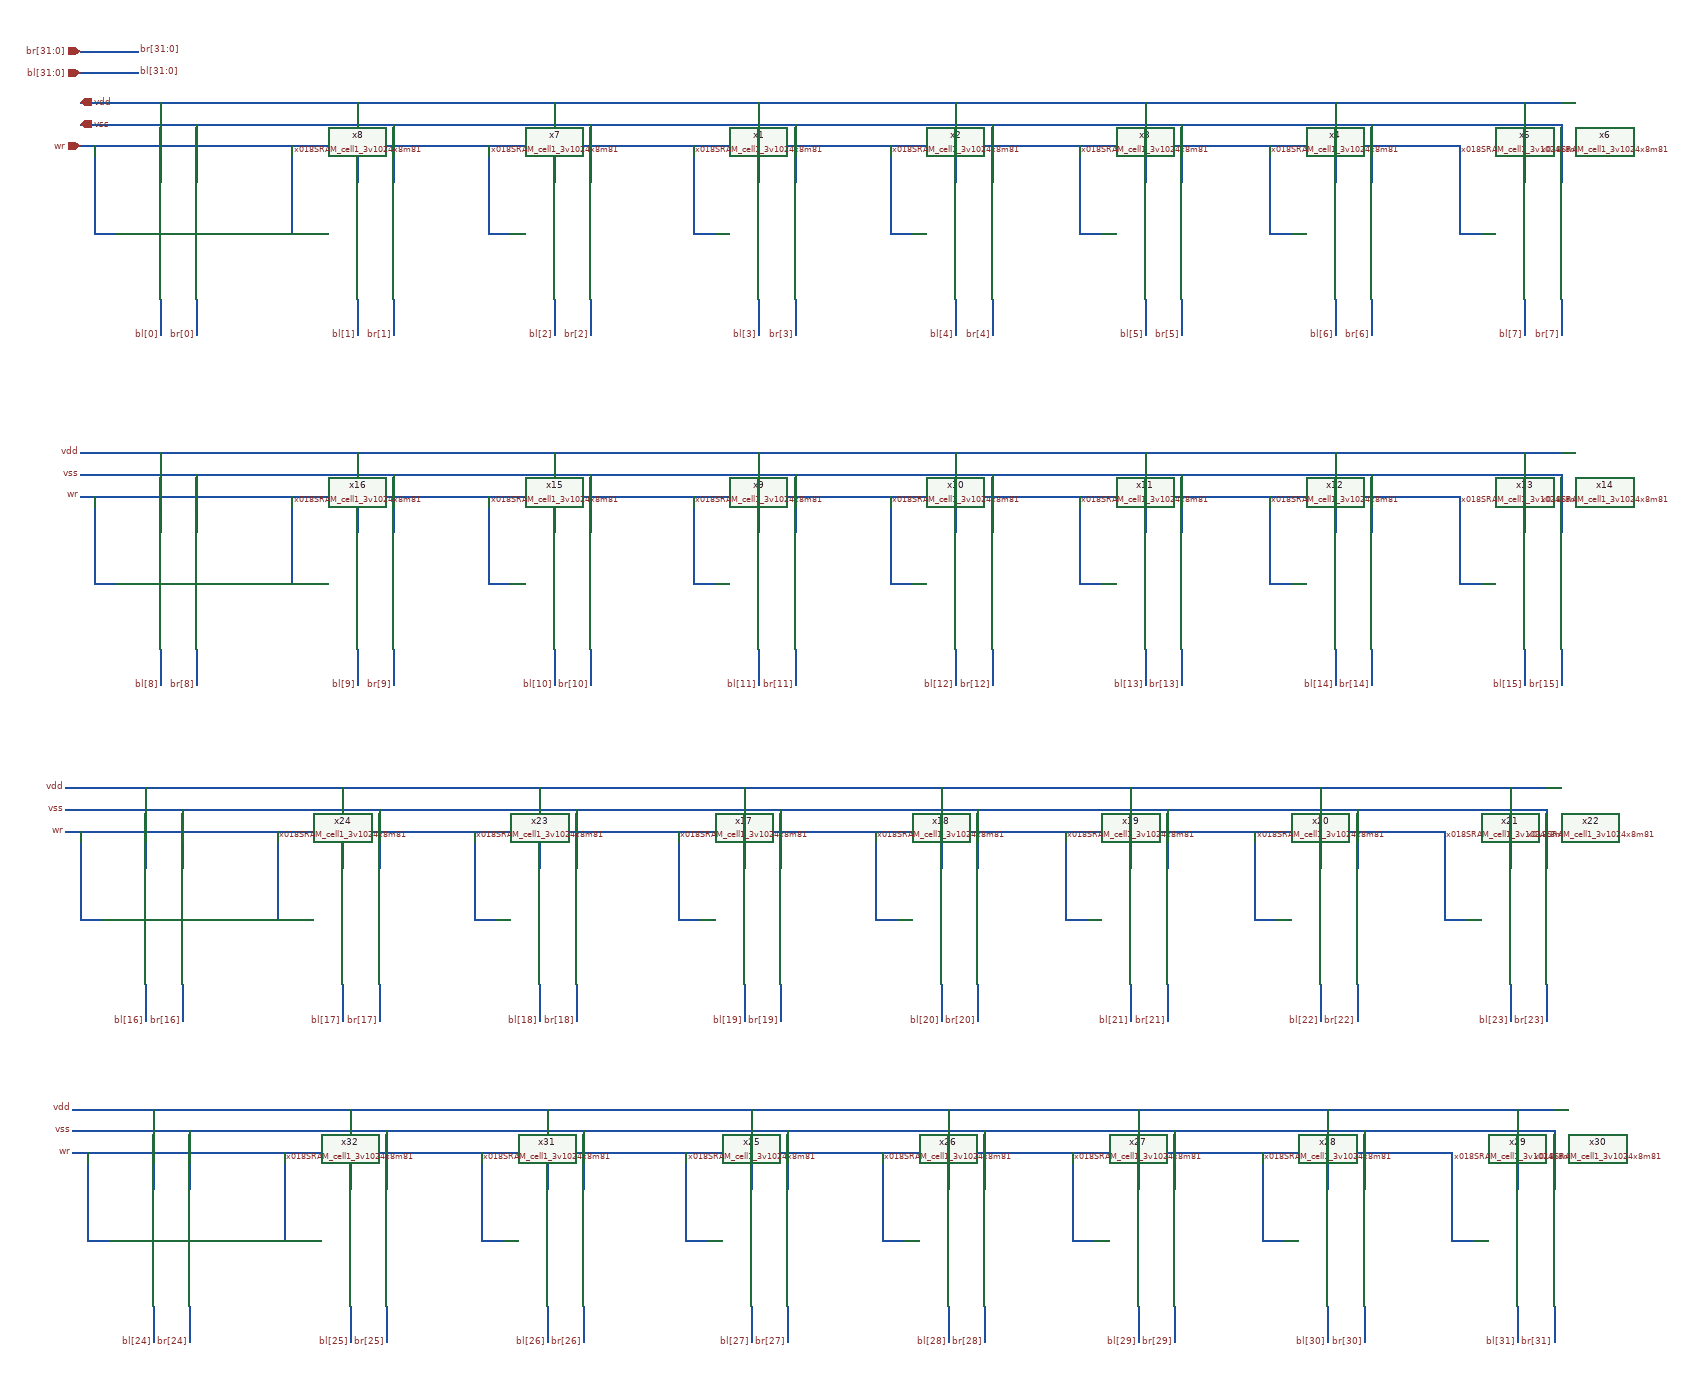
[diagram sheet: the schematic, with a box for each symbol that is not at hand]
v {xschem version=3.4.6 file_version=1.2}
G {}
K {}
V {}
S {}
E {}
N -770 -60 1260 -60 {lab=vss}
N -770 -90 1260 -90 {lab=vdd}
N -750 -30 -750 90 {lab=wr}
N -750 90 -720 90 {lab=wr}
N -660 -90 -660 20 {lab=vdd}
N -610 -60 -610 20 {lab=vss}
N -480 -30 -480 90 {lab=wr}
N -480 90 -450 90 {lab=wr}
N -390 -90 -390 20 {lab=vdd}
N -340 -60 -340 20 {lab=vss}
N -210 -30 -210 90 {lab=wr}
N -210 90 -180 90 {lab=wr}
N -120 -90 -120 20 {lab=vdd}
N -70 -60 -70 20 {lab=vss}
N 70 -30 70 90 {lab=wr}
N 70 90 100 90 {lab=wr}
N 160 -90 160 20 {lab=vdd}
N 210 -60 210 20 {lab=vss}
N 340 -30 340 90 {lab=wr}
N 340 90 370 90 {lab=wr}
N 430 -90 430 20 {lab=vdd}
N 480 -60 480 20 {lab=vss}
N 600 -30 600 90 {lab=wr}
N 600 90 630 90 {lab=wr}
N 690 -90 690 20 {lab=vdd}
N 740 -60 740 20 {lab=vss}
N 860 -30 860 90 {lab=wr}
N 860 90 890 90 {lab=wr}
N 950 -90 950 20 {lab=vdd}
N 1000 -60 1000 20 {lab=vss}
N 1120 -30 1120 90 {lab=wr}
N 1120 90 1150 90 {lab=wr}
N 1210 -90 1210 20 {lab=vdd}
N -660 180 -660 230 {lab=bl[0]}
N -610 180 -610 230 {lab=br[0]}
N -390 180 -390 230 {lab=bl[1]}
N -340 180 -340 230 {lab=br[1]}
N -120 180 -120 230 {lab=bl[2]}
N -70 180 -70 230 {lab=br[2]}
N 160 180 160 230 {lab=bl[3]}
N 210 180 210 230 {lab=br[3]}
N 430 180 430 230 {lab=bl[4]}
N 480 180 480 230 {lab=br[4]}
N 690 180 690 230 {lab=bl[5]}
N 740 180 740 230 {lab=br[5]}
N 950 180 950 230 {lab=bl[6]}
N 1000 180 1000 230 {lab=br[6]}
N 1210 180 1210 230 {lab=bl[7]}
N 1260 180 1260 230 {lab=br[7]}
N -770 -130 -690 -130 {lab=bl[31:0]}
N -770 -160 -690 -160 {lab=br[31:0]}
N -770 420 1260 420 {lab=vss}
N -770 390 1260 390 {lab=vdd}
N -750 450 -750 570 {lab=wr}
N -750 570 -720 570 {lab=wr}
N -660 390 -660 500 {lab=vdd}
N -610 420 -610 500 {lab=vss}
N -480 450 -480 570 {lab=wr}
N -480 570 -450 570 {lab=wr}
N -390 390 -390 500 {lab=vdd}
N -340 420 -340 500 {lab=vss}
N -210 450 -210 570 {lab=wr}
N -210 570 -180 570 {lab=wr}
N -120 390 -120 500 {lab=vdd}
N -70 420 -70 500 {lab=vss}
N 70 450 70 570 {lab=wr}
N 70 570 100 570 {lab=wr}
N 160 390 160 500 {lab=vdd}
N 210 420 210 500 {lab=vss}
N 340 450 340 570 {lab=wr}
N 340 570 370 570 {lab=wr}
N 430 390 430 500 {lab=vdd}
N 480 420 480 500 {lab=vss}
N 600 450 600 570 {lab=wr}
N 600 570 630 570 {lab=wr}
N 690 390 690 500 {lab=vdd}
N 740 420 740 500 {lab=vss}
N 860 450 860 570 {lab=wr}
N 860 570 890 570 {lab=wr}
N 950 390 950 500 {lab=vdd}
N 1000 420 1000 500 {lab=vss}
N 1120 450 1120 570 {lab=wr}
N 1120 570 1150 570 {lab=wr}
N 1210 390 1210 500 {lab=vdd}
N -660 660 -660 710 {lab=bl[8]}
N -610 660 -610 710 {lab=br[8]}
N -390 660 -390 710 {lab=bl[9]}
N -340 660 -340 710 {lab=br[9]}
N -120 660 -120 710 {lab=bl[10]}
N -70 660 -70 710 {lab=br[10]}
N 160 660 160 710 {lab=bl[11]}
N 210 660 210 710 {lab=br[11]}
N 430 660 430 710 {lab=bl[12]}
N 480 660 480 710 {lab=br[12]}
N 690 660 690 710 {lab=bl[13]}
N 740 660 740 710 {lab=br[13]}
N 950 660 950 710 {lab=bl[14]}
N 1000 660 1000 710 {lab=br[14]}
N 1210 660 1210 710 {lab=bl[15]}
N 1260 660 1260 710 {lab=br[15]}
N -790 880 1240 880 {lab=vss}
N -790 850 1240 850 {lab=vdd}
N -770 910 -770 1030 {lab=wr}
N -770 1030 -740 1030 {lab=wr}
N -680 850 -680 960 {lab=vdd}
N -630 880 -630 960 {lab=vss}
N -500 910 -500 1030 {lab=wr}
N -500 1030 -470 1030 {lab=wr}
N -410 850 -410 960 {lab=vdd}
N -360 880 -360 960 {lab=vss}
N -230 910 -230 1030 {lab=wr}
N -230 1030 -200 1030 {lab=wr}
N -140 850 -140 960 {lab=vdd}
N -90 880 -90 960 {lab=vss}
N 50 910 50 1030 {lab=wr}
N 50 1030 80 1030 {lab=wr}
N 140 850 140 960 {lab=vdd}
N 190 880 190 960 {lab=vss}
N 320 910 320 1030 {lab=wr}
N 320 1030 350 1030 {lab=wr}
N 410 850 410 960 {lab=vdd}
N 460 880 460 960 {lab=vss}
N 580 910 580 1030 {lab=wr}
N 580 1030 610 1030 {lab=wr}
N 670 850 670 960 {lab=vdd}
N 720 880 720 960 {lab=vss}
N 840 910 840 1030 {lab=wr}
N 840 1030 870 1030 {lab=wr}
N 930 850 930 960 {lab=vdd}
N 980 880 980 960 {lab=vss}
N 1100 910 1100 1030 {lab=wr}
N 1100 1030 1130 1030 {lab=wr}
N 1190 850 1190 960 {lab=vdd}
N -680 1120 -680 1170 {lab=bl[16]}
N -630 1120 -630 1170 {lab=br[16]}
N -410 1120 -410 1170 {lab=bl[17]}
N -360 1120 -360 1170 {lab=br[17]}
N -140 1120 -140 1170 {lab=bl[18]}
N -90 1120 -90 1170 {lab=br[18]}
N 140 1120 140 1170 {lab=bl[19]}
N 190 1120 190 1170 {lab=br[19]}
N 410 1120 410 1170 {lab=bl[20]}
N 460 1120 460 1170 {lab=br[20]}
N 670 1120 670 1170 {lab=bl[21]}
N 720 1120 720 1170 {lab=br[21]}
N 930 1120 930 1170 {lab=bl[22]}
N 980 1120 980 1170 {lab=br[22]}
N 1190 1120 1190 1170 {lab=bl[23]}
N 1240 1120 1240 1170 {lab=br[23]}
N -780 1320 1250 1320 {lab=vss}
N -780 1290 1250 1290 {lab=vdd}
N -760 1350 -760 1470 {lab=wr}
N -760 1470 -730 1470 {lab=wr}
N -670 1290 -670 1400 {lab=vdd}
N -620 1320 -620 1400 {lab=vss}
N -490 1350 -490 1470 {lab=wr}
N -490 1470 -460 1470 {lab=wr}
N -400 1290 -400 1400 {lab=vdd}
N -350 1320 -350 1400 {lab=vss}
N -220 1350 -220 1470 {lab=wr}
N -220 1470 -190 1470 {lab=wr}
N -130 1290 -130 1400 {lab=vdd}
N -80 1320 -80 1400 {lab=vss}
N 60 1350 60 1470 {lab=wr}
N 60 1470 90 1470 {lab=wr}
N 150 1290 150 1400 {lab=vdd}
N 200 1320 200 1400 {lab=vss}
N 330 1350 330 1470 {lab=wr}
N 330 1470 360 1470 {lab=wr}
N 420 1290 420 1400 {lab=vdd}
N 470 1320 470 1400 {lab=vss}
N 590 1350 590 1470 {lab=wr}
N 590 1470 620 1470 {lab=wr}
N 680 1290 680 1400 {lab=vdd}
N 730 1320 730 1400 {lab=vss}
N 850 1350 850 1470 {lab=wr}
N 850 1470 880 1470 {lab=wr}
N 940 1290 940 1400 {lab=vdd}
N 990 1320 990 1400 {lab=vss}
N 1110 1350 1110 1470 {lab=wr}
N 1110 1470 1140 1470 {lab=wr}
N 1200 1290 1200 1400 {lab=vdd}
N -670 1560 -670 1610 {lab=bl[24]}
N -620 1560 -620 1610 {lab=br[24]}
N -400 1560 -400 1610 {lab=bl[25]}
N -350 1560 -350 1610 {lab=br[25]}
N -130 1560 -130 1610 {lab=bl[26]}
N -80 1560 -80 1610 {lab=br[26]}
N 150 1560 150 1610 {lab=bl[27]}
N 200 1560 200 1610 {lab=br[27]}
N 420 1560 420 1610 {lab=bl[28]}
N 470 1560 470 1610 {lab=br[28]}
N 680 1560 680 1610 {lab=bl[29]}
N 730 1560 730 1610 {lab=br[29]}
N 940 1560 940 1610 {lab=bl[30]}
N 990 1560 990 1610 {lab=br[30]}
N 1200 1560 1200 1610 {lab=bl[31]}
N 1250 1560 1250 1610 {lab=br[31]}
N -770 -30 1120 -30 {lab=wr}
N -770 450 1120 450 {lab=wr}
N -790 910 1100 910 {lab=wr}
N -780 1350 1110 1350 {lab=wr}
N 1260 -60 1260 20 {lab=vss}
N 1260 420 1260 500 {lab=vss}
N 1240 880 1240 960 {lab=vss}
N 1250 1320 1250 1400 {lab=vss}
C {x018SRAM_cell1_3v1024x8m81.sym} -30 70 0 0 {name=x1}
C {x018SRAM_cell1_3v1024x8m81.sym} 250 70 0 0 {name=x2}
C {x018SRAM_cell1_3v1024x8m81.sym} 520 70 0 0 {name=x3}
C {x018SRAM_cell1_3v1024x8m81.sym} 780 70 0 0 {name=x4}
C {x018SRAM_cell1_3v1024x8m81.sym} 1040 70 0 0 {name=x5}
C {x018SRAM_cell1_3v1024x8m81.sym} 1300 70 0 0 {name=x6}
C {x018SRAM_cell1_3v1024x8m81.sym} -300 70 0 0 {name=x7}
C {x018SRAM_cell1_3v1024x8m81.sym} -570 70 0 0 {name=x8}
C {iopin.sym} -770 -90 0 1 {name=p1 lab=vdd}
C {iopin.sym} -770 -60 0 1 {name=p2 lab=vss}
C {ipin.sym} -770 -30 0 0 {name=p3 lab=wr}
C {iopin.sym} -770 -130 2 0 {name=p4 lab=bl[31:0]}
C {iopin.sym} -770 -160 2 0 {name=p5 lab=br[31:0]}
C {lab_pin.sym} -690 -160 0 1 {name=p6 sig_type=std_logic lab=br[31:0]}
C {lab_pin.sym} -690 -130 0 1 {name=p7 sig_type=std_logic lab=bl[31:0]}
C {lab_pin.sym} -660 230 3 0 {name=p8 sig_type=std_logic lab=bl[0]}
C {lab_pin.sym} -610 230 3 0 {name=p9 sig_type=std_logic lab=br[0]}
C {lab_pin.sym} -390 230 3 0 {name=p10 sig_type=std_logic lab=bl[1]}
C {lab_pin.sym} -340 230 3 0 {name=p11 sig_type=std_logic lab=br[1]}
C {lab_pin.sym} -120 230 3 0 {name=p12 sig_type=std_logic lab=bl[2]}
C {lab_pin.sym} -70 230 3 0 {name=p13 sig_type=std_logic lab=br[2]}
C {lab_pin.sym} 160 230 3 0 {name=p14 sig_type=std_logic lab=bl[3]}
C {lab_pin.sym} 210 230 3 0 {name=p15 sig_type=std_logic lab=br[3]}
C {lab_pin.sym} 430 230 3 0 {name=p16 sig_type=std_logic lab=bl[4]}
C {lab_pin.sym} 480 230 3 0 {name=p17 sig_type=std_logic lab=br[4]}
C {lab_pin.sym} 690 230 3 0 {name=p18 sig_type=std_logic lab=bl[5]}
C {lab_pin.sym} 740 230 3 0 {name=p19 sig_type=std_logic lab=br[5]}
C {lab_pin.sym} 950 230 3 0 {name=p20 sig_type=std_logic lab=bl[6]}
C {lab_pin.sym} 1000 230 3 0 {name=p21 sig_type=std_logic lab=br[6]}
C {lab_pin.sym} 1210 230 3 0 {name=p22 sig_type=std_logic lab=bl[7]}
C {lab_pin.sym} 1260 230 3 0 {name=p23 sig_type=std_logic lab=br[7]}
C {x018SRAM_cell1_3v1024x8m81.sym} -30 550 0 0 {name=x9}
C {x018SRAM_cell1_3v1024x8m81.sym} 250 550 0 0 {name=x10}
C {x018SRAM_cell1_3v1024x8m81.sym} 520 550 0 0 {name=x11}
C {x018SRAM_cell1_3v1024x8m81.sym} 780 550 0 0 {name=x12}
C {x018SRAM_cell1_3v1024x8m81.sym} 1040 550 0 0 {name=x13}
C {x018SRAM_cell1_3v1024x8m81.sym} 1300 550 0 0 {name=x14}
C {x018SRAM_cell1_3v1024x8m81.sym} -300 550 0 0 {name=x15}
C {x018SRAM_cell1_3v1024x8m81.sym} -570 550 0 0 {name=x16}
C {lab_pin.sym} -660 710 3 0 {name=p31 sig_type=std_logic lab=bl[8]}
C {lab_pin.sym} -610 710 3 0 {name=p32 sig_type=std_logic lab=br[8]}
C {lab_pin.sym} -390 710 3 0 {name=p33 sig_type=std_logic lab=bl[9]}
C {lab_pin.sym} -340 710 3 0 {name=p34 sig_type=std_logic lab=br[9]}
C {lab_pin.sym} -120 710 3 0 {name=p35 sig_type=std_logic lab=bl[10]}
C {lab_pin.sym} -70 710 3 0 {name=p36 sig_type=std_logic lab=br[10]}
C {lab_pin.sym} 160 710 3 0 {name=p37 sig_type=std_logic lab=bl[11]}
C {lab_pin.sym} 210 710 3 0 {name=p38 sig_type=std_logic lab=br[11]}
C {lab_pin.sym} 430 710 3 0 {name=p39 sig_type=std_logic lab=bl[12]}
C {lab_pin.sym} 480 710 3 0 {name=p40 sig_type=std_logic lab=br[12]}
C {lab_pin.sym} 690 710 3 0 {name=p41 sig_type=std_logic lab=bl[13]}
C {lab_pin.sym} 740 710 3 0 {name=p42 sig_type=std_logic lab=br[13]}
C {lab_pin.sym} 950 710 3 0 {name=p43 sig_type=std_logic lab=bl[14]}
C {lab_pin.sym} 1000 710 3 0 {name=p44 sig_type=std_logic lab=br[14]}
C {lab_pin.sym} 1210 710 3 0 {name=p45 sig_type=std_logic lab=bl[15]}
C {lab_pin.sym} 1260 710 3 0 {name=p46 sig_type=std_logic lab=br[15]}
C {lab_pin.sym} -770 390 0 0 {name=p24 sig_type=std_logic lab=vdd}
C {lab_pin.sym} -770 420 0 0 {name=p25 sig_type=std_logic lab=vss}
C {lab_pin.sym} -770 450 0 0 {name=p26 sig_type=std_logic lab=wr}
C {x018SRAM_cell1_3v1024x8m81.sym} -50 1010 0 0 {name=x17}
C {x018SRAM_cell1_3v1024x8m81.sym} 230 1010 0 0 {name=x18}
C {x018SRAM_cell1_3v1024x8m81.sym} 500 1010 0 0 {name=x19}
C {x018SRAM_cell1_3v1024x8m81.sym} 760 1010 0 0 {name=x20}
C {x018SRAM_cell1_3v1024x8m81.sym} 1020 1010 0 0 {name=x21}
C {x018SRAM_cell1_3v1024x8m81.sym} 1280 1010 0 0 {name=x22}
C {x018SRAM_cell1_3v1024x8m81.sym} -320 1010 0 0 {name=x23}
C {x018SRAM_cell1_3v1024x8m81.sym} -590 1010 0 0 {name=x24}
C {lab_pin.sym} -680 1170 3 0 {name=p27 sig_type=std_logic lab=bl[16]}
C {lab_pin.sym} -630 1170 3 0 {name=p28 sig_type=std_logic lab=br[16]}
C {lab_pin.sym} -410 1170 3 0 {name=p29 sig_type=std_logic lab=bl[17]}
C {lab_pin.sym} -360 1170 3 0 {name=p30 sig_type=std_logic lab=br[17]}
C {lab_pin.sym} -140 1170 3 0 {name=p47 sig_type=std_logic lab=bl[18]}
C {lab_pin.sym} -90 1170 3 0 {name=p48 sig_type=std_logic lab=br[18]}
C {lab_pin.sym} 140 1170 3 0 {name=p49 sig_type=std_logic lab=bl[19]}
C {lab_pin.sym} 190 1170 3 0 {name=p50 sig_type=std_logic lab=br[19]}
C {lab_pin.sym} 410 1170 3 0 {name=p51 sig_type=std_logic lab=bl[20]}
C {lab_pin.sym} 460 1170 3 0 {name=p52 sig_type=std_logic lab=br[20]}
C {lab_pin.sym} 670 1170 3 0 {name=p53 sig_type=std_logic lab=bl[21]}
C {lab_pin.sym} 720 1170 3 0 {name=p54 sig_type=std_logic lab=br[21]}
C {lab_pin.sym} 930 1170 3 0 {name=p55 sig_type=std_logic lab=bl[22]}
C {lab_pin.sym} 980 1170 3 0 {name=p56 sig_type=std_logic lab=br[22]}
C {lab_pin.sym} 1190 1170 3 0 {name=p57 sig_type=std_logic lab=bl[23]}
C {lab_pin.sym} 1240 1170 3 0 {name=p58 sig_type=std_logic lab=br[23]}
C {lab_pin.sym} -790 850 0 0 {name=p59 sig_type=std_logic lab=vdd}
C {lab_pin.sym} -790 880 0 0 {name=p60 sig_type=std_logic lab=vss}
C {lab_pin.sym} -790 910 0 0 {name=p61 sig_type=std_logic lab=wr}
C {x018SRAM_cell1_3v1024x8m81.sym} -40 1450 0 0 {name=x25}
C {x018SRAM_cell1_3v1024x8m81.sym} 240 1450 0 0 {name=x26}
C {x018SRAM_cell1_3v1024x8m81.sym} 510 1450 0 0 {name=x27}
C {x018SRAM_cell1_3v1024x8m81.sym} 770 1450 0 0 {name=x28}
C {x018SRAM_cell1_3v1024x8m81.sym} 1030 1450 0 0 {name=x29}
C {x018SRAM_cell1_3v1024x8m81.sym} 1290 1450 0 0 {name=x30}
C {x018SRAM_cell1_3v1024x8m81.sym} -310 1450 0 0 {name=x31}
C {x018SRAM_cell1_3v1024x8m81.sym} -580 1450 0 0 {name=x32}
C {lab_pin.sym} -670 1610 3 0 {name=p62 sig_type=std_logic lab=bl[24]}
C {lab_pin.sym} -620 1610 3 0 {name=p63 sig_type=std_logic lab=br[24]}
C {lab_pin.sym} -400 1610 3 0 {name=p64 sig_type=std_logic lab=bl[25]}
C {lab_pin.sym} -350 1610 3 0 {name=p65 sig_type=std_logic lab=br[25]}
C {lab_pin.sym} -130 1610 3 0 {name=p66 sig_type=std_logic lab=bl[26]}
C {lab_pin.sym} -80 1610 3 0 {name=p67 sig_type=std_logic lab=br[26]}
C {lab_pin.sym} 150 1610 3 0 {name=p68 sig_type=std_logic lab=bl[27]}
C {lab_pin.sym} 200 1610 3 0 {name=p69 sig_type=std_logic lab=br[27]}
C {lab_pin.sym} 420 1610 3 0 {name=p70 sig_type=std_logic lab=bl[28]}
C {lab_pin.sym} 470 1610 3 0 {name=p71 sig_type=std_logic lab=br[28]}
C {lab_pin.sym} 680 1610 3 0 {name=p72 sig_type=std_logic lab=bl[29]}
C {lab_pin.sym} 730 1610 3 0 {name=p73 sig_type=std_logic lab=br[29]}
C {lab_pin.sym} 940 1610 3 0 {name=p74 sig_type=std_logic lab=bl[30]}
C {lab_pin.sym} 990 1610 3 0 {name=p75 sig_type=std_logic lab=br[30]}
C {lab_pin.sym} 1200 1610 3 0 {name=p76 sig_type=std_logic lab=bl[31]}
C {lab_pin.sym} 1250 1610 3 0 {name=p77 sig_type=std_logic lab=br[31]}
C {lab_pin.sym} -780 1290 0 0 {name=p78 sig_type=std_logic lab=vdd}
C {lab_pin.sym} -780 1320 0 0 {name=p79 sig_type=std_logic lab=vss}
C {lab_pin.sym} -780 1350 0 0 {name=p80 sig_type=std_logic lab=wr}
